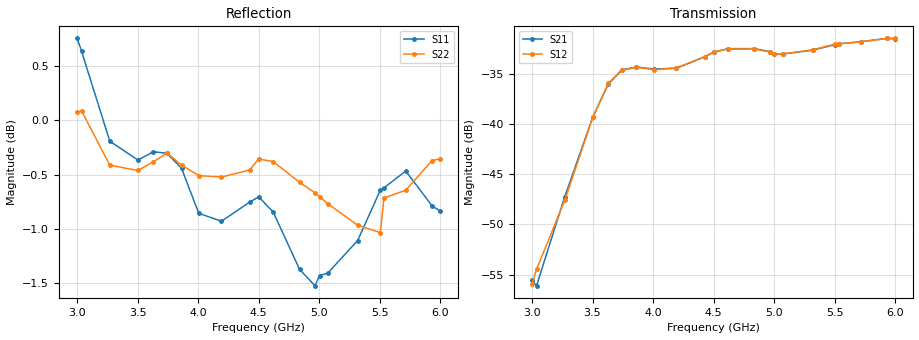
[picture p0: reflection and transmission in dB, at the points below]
!  27/11/2025  10:45:10
! Ref Plane: 0.000 mm
# MHZ S MA R  50
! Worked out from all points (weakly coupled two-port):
!   401 points, 3 GHz to 6 GHz, reference 50 ohm
!   highest |S21| = -31.51 dB at 5.933 GHz (marker M1); lowest = -56.1 dB at 3.038 GHz (marker M2)
!   lowest |S11| = -1.5 dB at 4.965 GHz (marker M3), VSWR 11.44, Z = 10.4 - j58.2 ohm
!   |S11| at or under -10 dB: nowhere
!   |S22| runs from -1.1 to 0.1 dB; largest |S21 - S12| = 0.001
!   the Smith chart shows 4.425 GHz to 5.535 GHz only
!   S11 on the Smith chart (normalised r, x): 4.425 GHz: 0.08, +0.95; 4.62 GHz: 0.80, +3.85; 4.838 GHz: 0.61, -2.54; 5.07 GHz: 0.12, -0.69; 5.317 GHz: 0.06, -0.01; 5.535 GHz: 0.05, +0.58
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3000  1.091 -133.8  0.001665 47.4  0.001598 51.3  1.009 -101.8
3037.5  1.076 -143.8  0.001567 39.9  0.001891 44.3  1.01 -107.8
3270  0.9782 155.3  0.004336 -17.2  0.004159 -12.7  0.9537 -167.3
3502.5  0.9589 70.0  0.01082 -96.1  0.01075 -95.3  0.9483 116.3
3630  0.9673 14.8  0.01576 -152.2  0.01588 -151.0  0.9571 61.4
3742.5  0.9658 -35.4  0.01858 157.1  0.01845 158.9  0.966 12.9
3862.5  0.9506 -83.5  0.01914 107.2  0.01909 108.9  0.9538 -36.0
4005  0.9062 -134.5  0.01874 56.7  0.01857 57.8  0.9432 -85.3
4192.5  0.8986 166.5  0.01887 -0.3  0.01896 1.4  0.9417 -143.1
4425  0.917 92.6  0.02152 -70.4  0.02156 -69.0  0.9488 146.6
4500  0.9221 68.0  0.02267 -94.8  0.02273 -93.3  0.9599 123.3
4620  0.9074 28.0  0.02364 -133.8  0.02358 -132.5  0.9573 85.7
4837.5  0.8539 -41.0  0.02364 157.5  0.02351 159.0  0.9365 20.0
4965  0.8392 -80.3  0.02286 120.8  0.02275 122.2  0.926 -16.2
5002.5  0.8482 -91.6  0.02226 110.4  0.02213 111.8  0.9224 -27.7
5070  0.8504 -110.2  0.02223 92.3  0.02224 93.5  0.9155 -46.8
5317.5  0.8804 -178.6  0.0232 24.7  0.02334 26.3  0.8949 -117.9
5505  0.9287 126.4  0.02477 -27.7  0.0249 -26.2  0.8878 -167.4
5535  0.931 119.5  0.025 -35.8  0.02496 -34.4  0.921 -175.0
5715  0.9478 67.3  0.02556 -88.3  0.02557 -86.5  0.9287 132.8
5932.5  0.9133 5.1  0.02657 -150.4  0.02659 -148.8  0.9584 75.3
6000  0.9083 -14.8  0.02651 -169.5  0.02656 -168.1  0.9601 58.1
